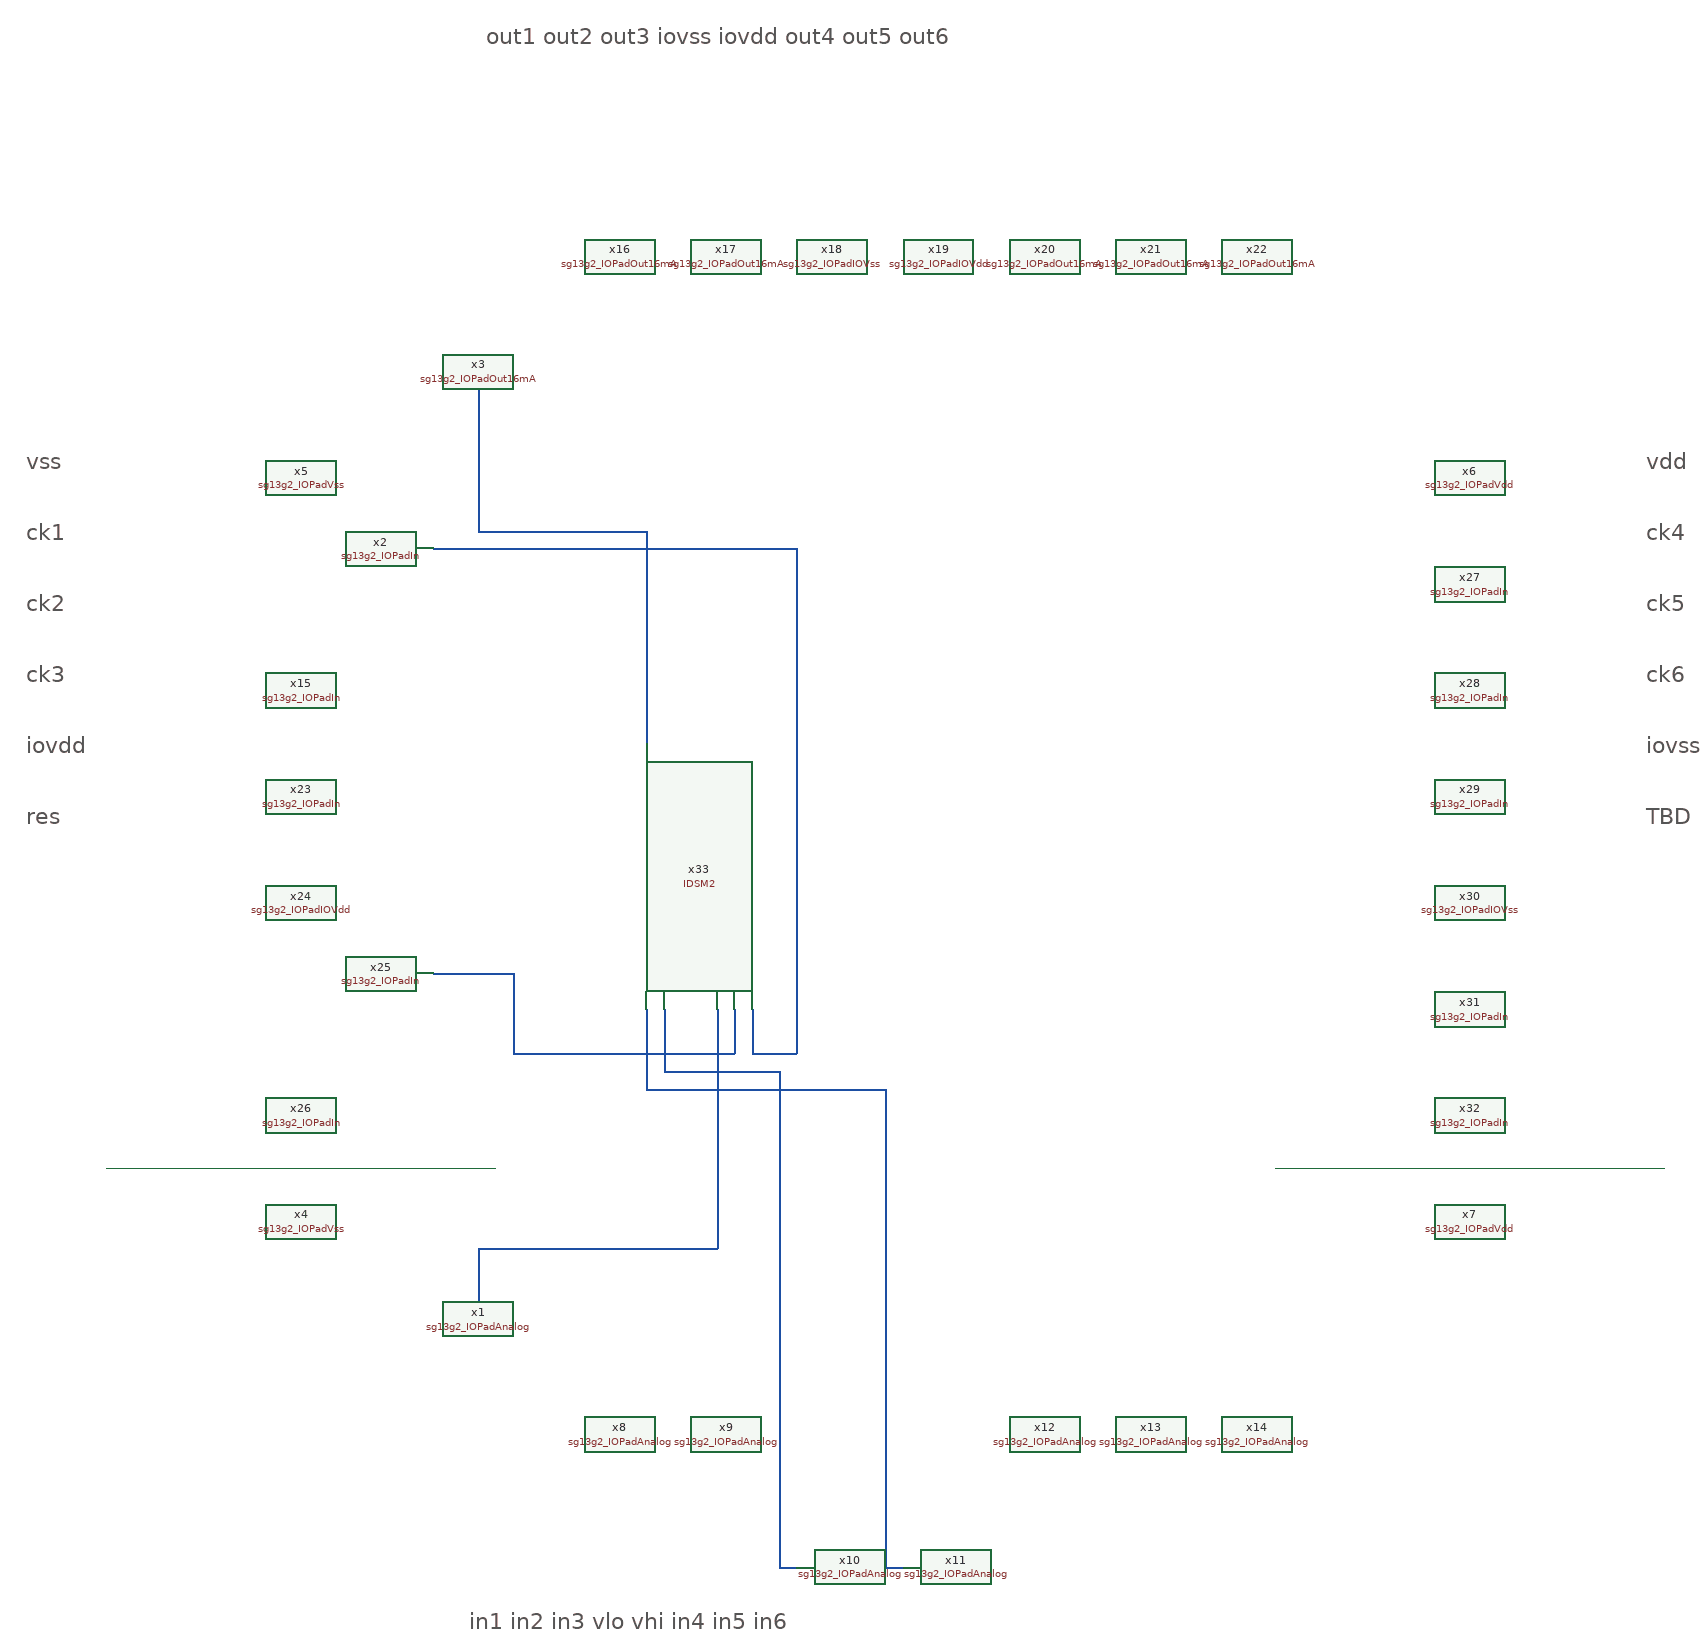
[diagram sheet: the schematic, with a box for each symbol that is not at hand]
v {xschem version=3.4.5 file_version=1.2
}
G {}
K {}
V {}
S {}
E {}
L 4 130 -670 570 -670 {}
L 4 1450 -670 1890 -670 {}
T {in1   in2   in3   vlo   vhi   in4   in5   in6} 540 -170 0 0 0.95 0.95 {}
T {out1 out2 out3 iovss iovdd out4 out5 out6} 560 -1960 0 0 0.85 0.85 {}
T {vss

ck1

ck2

ck3

iovdd

res

TBD

avss} 40 -1480 0 0 1 1 {}
T {vdd

ck4

ck5

ck6

iovss

TBD

TBD

avdd} 1870 -1480 0 0 1 1 {}
N 550 -1550 550 -1390 {
lab=#net1}
N 550 -1390 740 -1390 {
lab=#net1}
N 740 -1390 740 -1150 {
lab=#net1}
N 890 -220 910 -220 {
lab=#net2}
N 890 -780 890 -220 {
lab=#net2}
N 760 -780 890 -780 {
lab=#net2}
N 760 -850 760 -780 {
lab=#net2}
N 1010 -220 1030 -220 {
lab=#net3}
N 1010 -760 1010 -220 {
lab=#net3}
N 740 -760 1010 -760 {
lab=#net3}
N 740 -850 740 -760 {
lab=#net3}
N 550 -580 550 -520 {
lab=#net4}
N 550 -580 820 -580 {
lab=#net4}
N 820 -850 820 -580 {
lab=#net4}
N 590 -800 840 -800 {
lab=#net5}
N 840 -850 840 -800 {
lab=#net5}
N 860 -850 860 -800 {
lab=#net6}
N 500 -1370 910 -1370 {
lab=#net6}
N 910 -1370 910 -800 {
lab=#net6}
N 860 -800 910 -800 {
lab=#net6}
N 500 -890 590 -890 {
lab=#net5}
N 590 -890 590 -800 {
lab=#net5}
C {devices/title.sym} 160 -40 0 0 {name=l1 author="Boris Murmann"}
C {sg13g2_IOPadAnalog.sym} 590 -370 3 0 {name=x1}
C {sg13g2_IOPadIn.sym} 350 -1330 0 0 {name=x2}
C {sg13g2_IOPadOut16mA.sym} 590 -1700 3 1 {name=x3}
C {sg13g2_IOPadVss.sym} 350 -610 0 0 {name=x4}
C {sg13g2_IOPadVdd.sym} 1670 -610 0 1 {name=x7}
C {sg13g2_IOPadAnalog.sym} 710 -370 3 0 {name=x8}
C {sg13g2_IOPadAnalog.sym} 830 -370 3 0 {name=x9}
C {sg13g2_IOPadAnalog.sym} 950 -370 3 0 {name=x10}
C {sg13g2_IOPadAnalog.sym} 1070 -370 3 0 {name=x11}
C {sg13g2_IOPadAnalog.sym} 1190 -370 3 0 {name=x12}
C {sg13g2_IOPadAnalog.sym} 1310 -370 3 0 {name=x13}
C {sg13g2_IOPadAnalog.sym} 1430 -370 3 0 {name=x14}
C {sg13g2_IOPadOut16mA.sym} 710 -1700 3 1 {name=x16}
C {sg13g2_IOPadOut16mA.sym} 830 -1700 3 1 {name=x17}
C {sg13g2_IOPadIOVss.sym} 950 -1700 3 1 {name=x18}
C {sg13g2_IOPadIOVdd.sym} 1070 -1700 3 1 {name=x19}
C {sg13g2_IOPadOut16mA.sym} 1190 -1700 3 1 {name=x20}
C {sg13g2_IOPadOut16mA.sym} 1310 -1700 3 1 {name=x21}
C {sg13g2_IOPadOut16mA.sym} 1430 -1700 3 1 {name=x22}
C {sg13g2_IOPadVss.sym} 350 -1450 0 0 {name=x5}
C {sg13g2_IOPadVdd.sym} 1670 -1450 0 1 {name=x6}
C {sg13g2_IOPadIn.sym} 350 -1210 0 0 {name=x15}
C {sg13g2_IOPadIn.sym} 350 -1090 0 0 {name=x23}
C {sg13g2_IOPadIOVdd.sym} 350 -970 0 0 {name=x24}
C {sg13g2_IOPadIn.sym} 350 -850 0 0 {name=x25}
C {sg13g2_IOPadIn.sym} 350 -730 0 0 {name=x26}
C {sg13g2_IOPadIn.sym} 1670 -1330 0 1 {name=x27}
C {sg13g2_IOPadIn.sym} 1670 -1210 0 1 {name=x28}
C {sg13g2_IOPadIn.sym} 1670 -1090 0 1 {name=x29}
C {sg13g2_IOPadIOVss.sym} 1670 -970 0 1 {name=x30}
C {sg13g2_IOPadIn.sym} 1670 -850 0 1 {name=x31}
C {sg13g2_IOPadIn.sym} 1670 -730 0 1 {name=x32}
C {/foss/designs/EE628/5_Design/3_Real_circuits/IDSM2.sym} 800 -1000 3 0 {name=x33}
